One B-rep face of a CAD part: STEP entity #9798.
In plain terms, the planar face has unit normal (0, 1, 0).
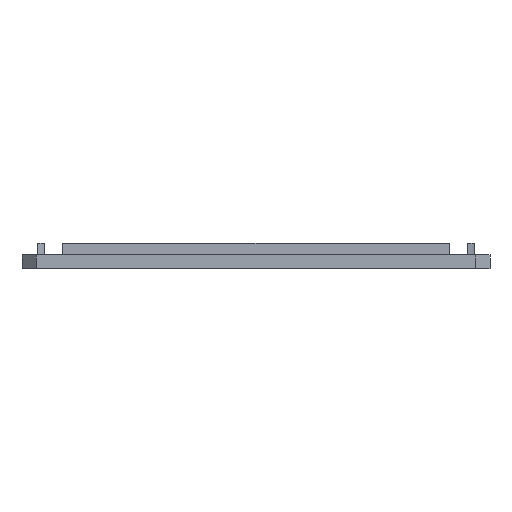
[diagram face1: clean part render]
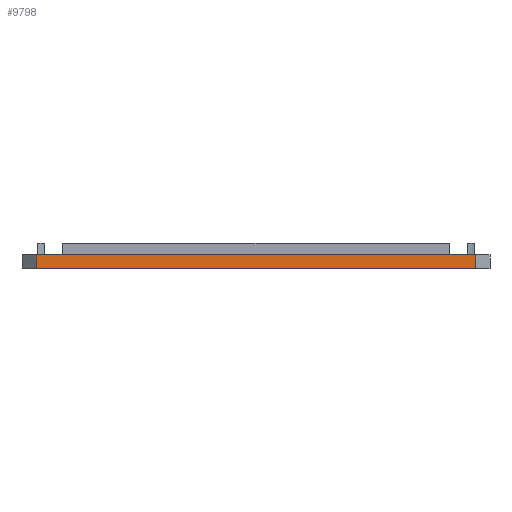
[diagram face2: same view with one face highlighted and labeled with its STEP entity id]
Its self-contained STEP definition (entity closure, numbers rounded to 3 decimals):
#144 = PLANE('',#145);
#145 = AXIS2_PLACEMENT_3D('',#146,#147,#148);
#146 = CARTESIAN_POINT('',(0.,0.,28.));
#147 = DIRECTION('',(0.,0.,1.));
#148 = DIRECTION('',(1.,0.,-0.));
#337 = VERTEX_POINT('',#338);
#338 = CARTESIAN_POINT('',(38.5,55.,28.));
#352 = PLANE('',#353);
#353 = AXIS2_PLACEMENT_3D('',#354,#355,#356);
#354 = CARTESIAN_POINT('',(41.,52.5,28.));
#355 = DIRECTION('',(-0.707,-0.707,0.));
#356 = DIRECTION('',(-0.707,0.707,0.));
#364 = EDGE_CURVE('',#337,#365,#367,.T.);
#365 = VERTEX_POINT('',#366);
#366 = CARTESIAN_POINT('',(-38.5,55.,28.));
#367 = SURFACE_CURVE('',#368,(#372,#379),.PCURVE_S1.);
#368 = LINE('',#369,#370);
#369 = CARTESIAN_POINT('',(38.5,55.,28.));
#370 = VECTOR('',#371,1.);
#371 = DIRECTION('',(-1.,0.,0.));
#372 = PCURVE('',#144,#373);
#373 = DEFINITIONAL_REPRESENTATION('',(#374),#378);
#374 = LINE('',#375,#376);
#375 = CARTESIAN_POINT('',(38.5,55.));
#376 = VECTOR('',#377,1.);
#377 = DIRECTION('',(-1.,0.));
#378 = ( GEOMETRIC_REPRESENTATION_CONTEXT(2) 
PARAMETRIC_REPRESENTATION_CONTEXT() REPRESENTATION_CONTEXT('2D SPACE',''
  ) );
#379 = PCURVE('',#380,#385);
#380 = PLANE('',#381);
#381 = AXIS2_PLACEMENT_3D('',#382,#383,#384);
#382 = CARTESIAN_POINT('',(38.5,55.,28.));
#383 = DIRECTION('',(0.,-1.,0.));
#384 = DIRECTION('',(-1.,0.,0.));
#385 = DEFINITIONAL_REPRESENTATION('',(#386),#390);
#386 = LINE('',#387,#388);
#387 = CARTESIAN_POINT('',(0.,-0.));
#388 = VECTOR('',#389,1.);
#389 = DIRECTION('',(1.,0.));
#390 = ( GEOMETRIC_REPRESENTATION_CONTEXT(2) 
PARAMETRIC_REPRESENTATION_CONTEXT() REPRESENTATION_CONTEXT('2D SPACE',''
  ) );
#408 = PLANE('',#409);
#409 = AXIS2_PLACEMENT_3D('',#410,#411,#412);
#410 = CARTESIAN_POINT('',(-38.5,55.,28.));
#411 = DIRECTION('',(0.707,-0.707,0.));
#412 = DIRECTION('',(-0.707,-0.707,0.));
#9311 = PLANE('',#9312);
#9312 = AXIS2_PLACEMENT_3D('',#9313,#9314,#9315);
#9313 = CARTESIAN_POINT('',(0.,0.,30.4)
  );
#9314 = DIRECTION('',(0.,0.,1.));
#9315 = DIRECTION('',(1.,0.,-0.));
#9704 = EDGE_CURVE('',#365,#9705,#9707,.T.);
#9705 = VERTEX_POINT('',#9706);
#9706 = CARTESIAN_POINT('',(-38.5,55.,30.4));
#9707 = SURFACE_CURVE('',#9708,(#9712,#9719),.PCURVE_S1.);
#9708 = LINE('',#9709,#9710);
#9709 = CARTESIAN_POINT('',(-38.5,55.,28.));
#9710 = VECTOR('',#9711,1.);
#9711 = DIRECTION('',(0.,0.,1.));
#9712 = PCURVE('',#408,#9713);
#9713 = DEFINITIONAL_REPRESENTATION('',(#9714),#9718);
#9714 = LINE('',#9715,#9716);
#9715 = CARTESIAN_POINT('',(0.,0.));
#9716 = VECTOR('',#9717,1.);
#9717 = DIRECTION('',(0.,-1.));
#9718 = ( GEOMETRIC_REPRESENTATION_CONTEXT(2) 
PARAMETRIC_REPRESENTATION_CONTEXT() REPRESENTATION_CONTEXT('2D SPACE',''
  ) );
#9719 = PCURVE('',#380,#9720);
#9720 = DEFINITIONAL_REPRESENTATION('',(#9721),#9725);
#9721 = LINE('',#9722,#9723);
#9722 = CARTESIAN_POINT('',(77.,0.));
#9723 = VECTOR('',#9724,1.);
#9724 = DIRECTION('',(0.,-1.));
#9725 = ( GEOMETRIC_REPRESENTATION_CONTEXT(2) 
PARAMETRIC_REPRESENTATION_CONTEXT() REPRESENTATION_CONTEXT('2D SPACE',''
  ) );
#9755 = VERTEX_POINT('',#9756);
#9756 = CARTESIAN_POINT('',(38.5,55.,30.4));
#9777 = EDGE_CURVE('',#337,#9755,#9778,.T.);
#9778 = SURFACE_CURVE('',#9779,(#9783,#9790),.PCURVE_S1.);
#9779 = LINE('',#9780,#9781);
#9780 = CARTESIAN_POINT('',(38.5,55.,28.));
#9781 = VECTOR('',#9782,1.);
#9782 = DIRECTION('',(0.,0.,1.));
#9783 = PCURVE('',#352,#9784);
#9784 = DEFINITIONAL_REPRESENTATION('',(#9785),#9789);
#9785 = LINE('',#9786,#9787);
#9786 = CARTESIAN_POINT('',(3.536,0.));
#9787 = VECTOR('',#9788,1.);
#9788 = DIRECTION('',(0.,-1.));
#9789 = ( GEOMETRIC_REPRESENTATION_CONTEXT(2) 
PARAMETRIC_REPRESENTATION_CONTEXT() REPRESENTATION_CONTEXT('2D SPACE',''
  ) );
#9790 = PCURVE('',#380,#9791);
#9791 = DEFINITIONAL_REPRESENTATION('',(#9792),#9796);
#9792 = LINE('',#9793,#9794);
#9793 = CARTESIAN_POINT('',(0.,-0.));
#9794 = VECTOR('',#9795,1.);
#9795 = DIRECTION('',(0.,-1.));
#9796 = ( GEOMETRIC_REPRESENTATION_CONTEXT(2) 
PARAMETRIC_REPRESENTATION_CONTEXT() REPRESENTATION_CONTEXT('2D SPACE',''
  ) );
#9798 = ADVANCED_FACE('',(#9799),#380,.F.);
#9799 = FACE_BOUND('',#9800,.F.);
#9800 = EDGE_LOOP('',(#9801,#9802,#9823,#9824));
#9801 = ORIENTED_EDGE('',*,*,#9777,.T.);
#9802 = ORIENTED_EDGE('',*,*,#9803,.T.);
#9803 = EDGE_CURVE('',#9755,#9705,#9804,.T.);
#9804 = SURFACE_CURVE('',#9805,(#9809,#9816),.PCURVE_S1.);
#9805 = LINE('',#9806,#9807);
#9806 = CARTESIAN_POINT('',(38.5,55.,30.4));
#9807 = VECTOR('',#9808,1.);
#9808 = DIRECTION('',(-1.,0.,0.));
#9809 = PCURVE('',#380,#9810);
#9810 = DEFINITIONAL_REPRESENTATION('',(#9811),#9815);
#9811 = LINE('',#9812,#9813);
#9812 = CARTESIAN_POINT('',(0.,-2.4));
#9813 = VECTOR('',#9814,1.);
#9814 = DIRECTION('',(1.,0.));
#9815 = ( GEOMETRIC_REPRESENTATION_CONTEXT(2) 
PARAMETRIC_REPRESENTATION_CONTEXT() REPRESENTATION_CONTEXT('2D SPACE',''
  ) );
#9816 = PCURVE('',#9311,#9817);
#9817 = DEFINITIONAL_REPRESENTATION('',(#9818),#9822);
#9818 = LINE('',#9819,#9820);
#9819 = CARTESIAN_POINT('',(38.5,55.));
#9820 = VECTOR('',#9821,1.);
#9821 = DIRECTION('',(-1.,0.));
#9822 = ( GEOMETRIC_REPRESENTATION_CONTEXT(2) 
PARAMETRIC_REPRESENTATION_CONTEXT() REPRESENTATION_CONTEXT('2D SPACE',''
  ) );
#9823 = ORIENTED_EDGE('',*,*,#9704,.F.);
#9824 = ORIENTED_EDGE('',*,*,#364,.F.);
